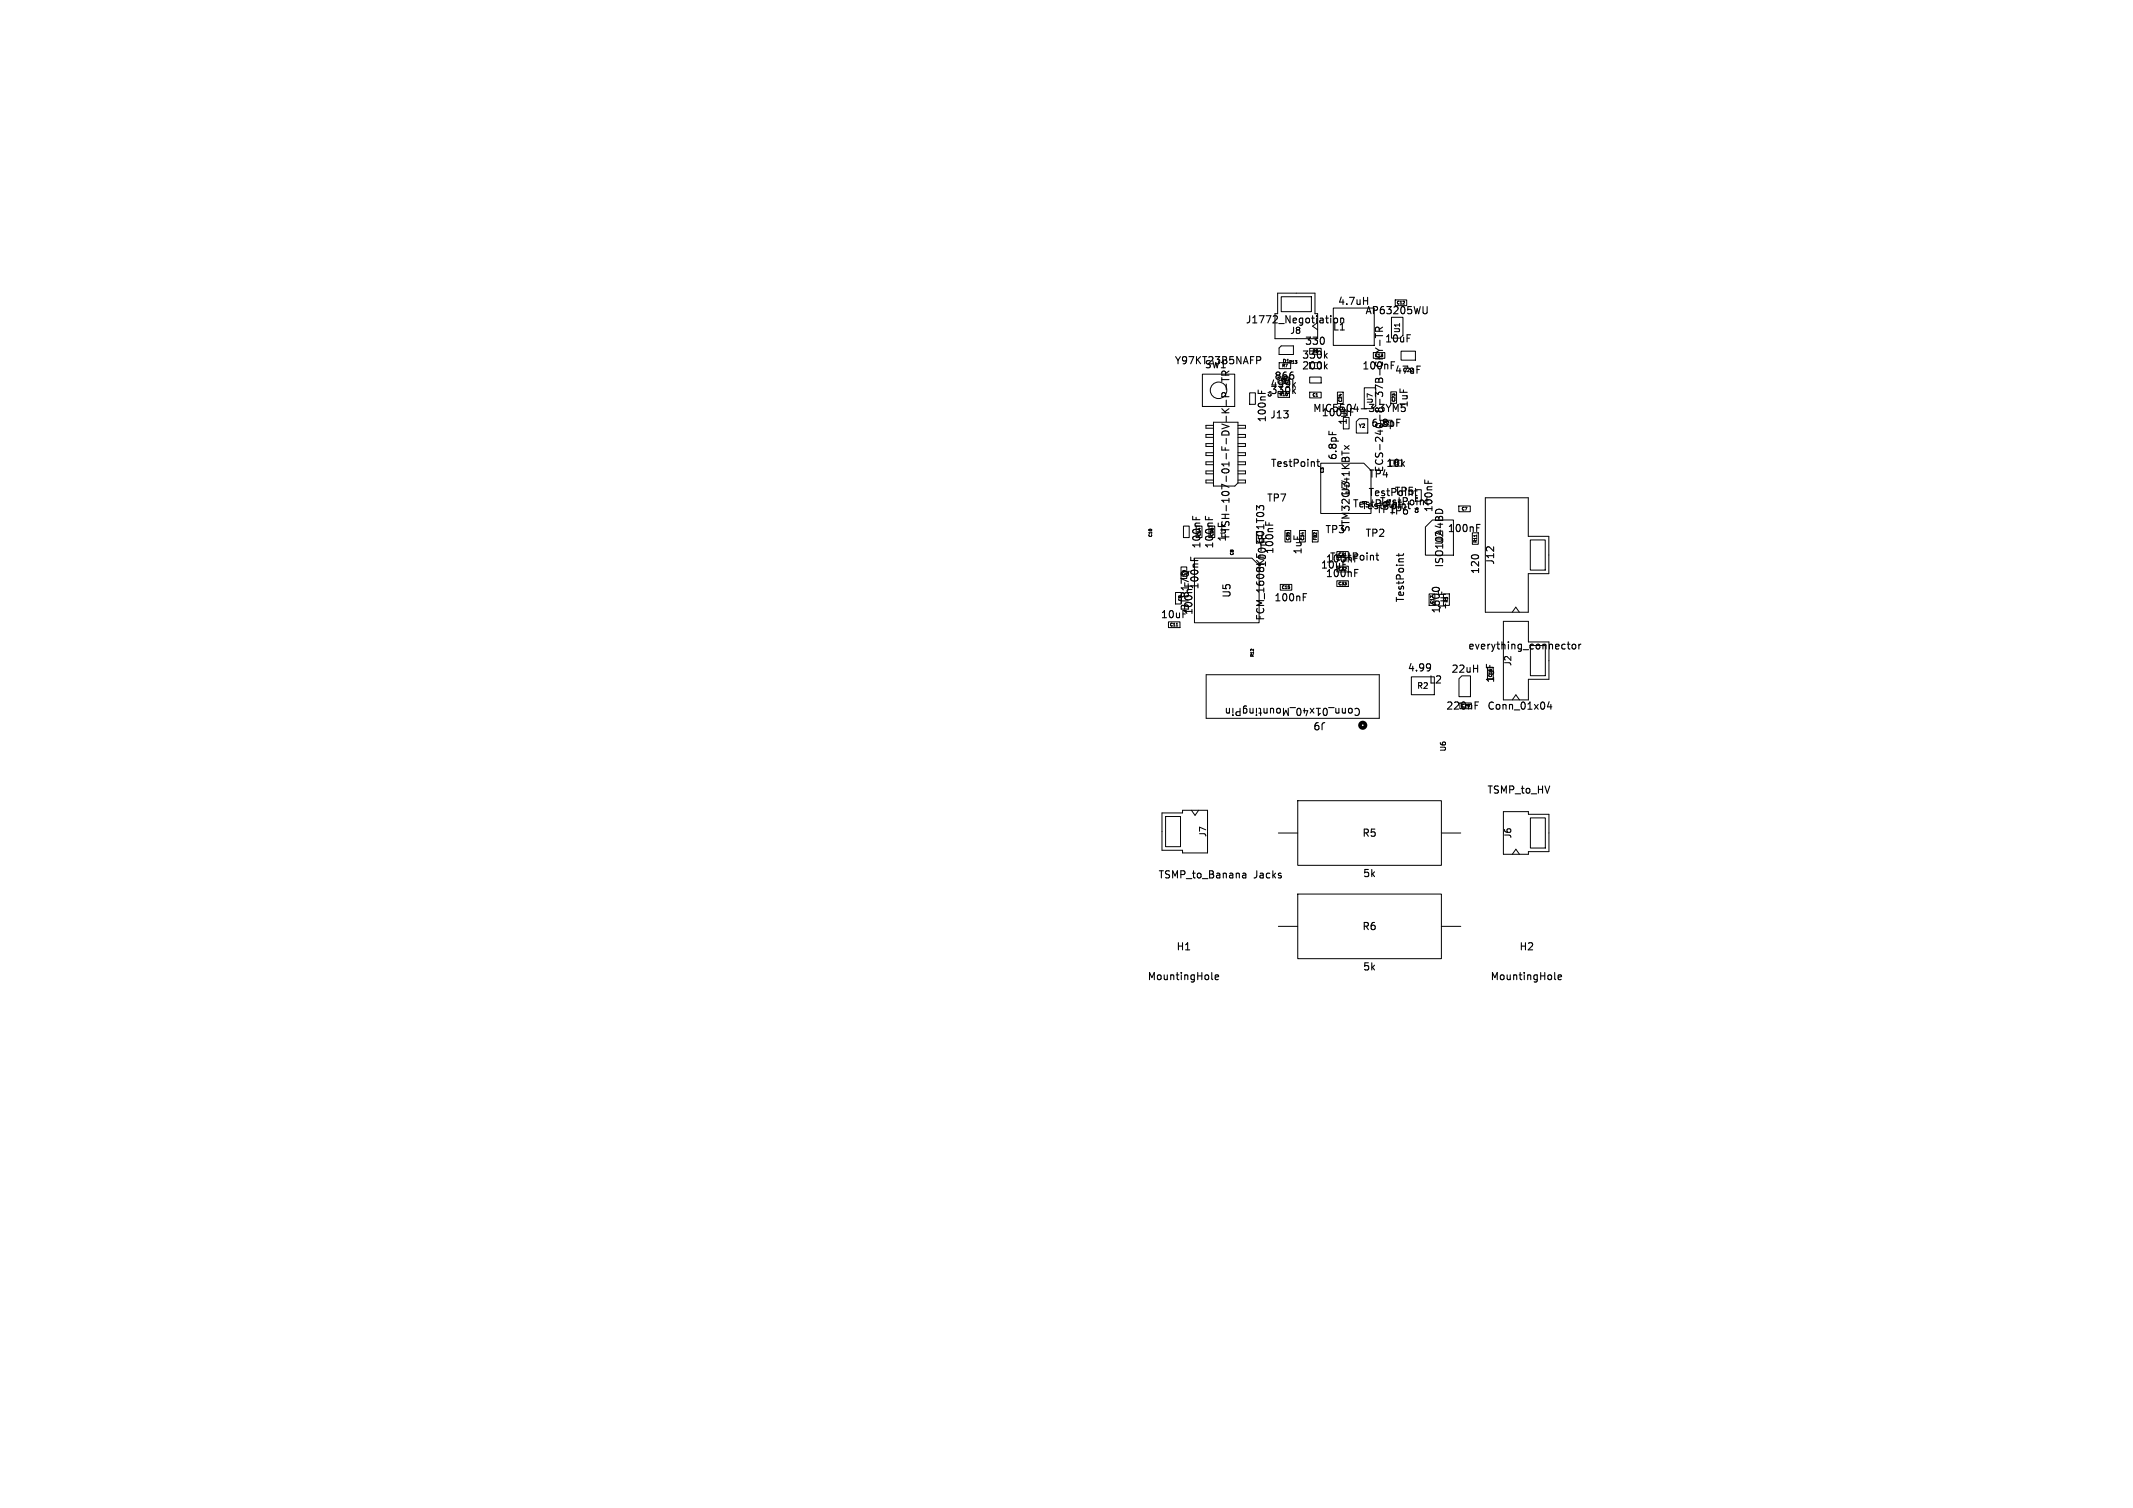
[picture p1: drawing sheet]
<svg xmlns="http://www.w3.org/2000/svg" width="297mm" height="210mm" viewBox="0 0 297 210" stroke-linecap="round" stroke-linejoin="round" font-family="sans-serif">
<defs><g id="words">
<g font-size="1.4">
<text x="173.4" y="45.2">J1772_Negotiation</text>
<text x="185.5" y="46.2">L1</text>
<text x="186.2" y="42.7">4.7uH</text>
<text x="190" y="44">AP63205WU</text>
<text x="192.8" y="47.9">10uF</text>
<text x="163.5" y="50.9">Y97KT23B5NAFP</text>
<text x="167.6" y="51.5">SW1</text>
<text x="177.4" y="53.1">866</text>
<text x="178.5" y="53.7">D</text>
<text x="181.2" y="50.2">330k</text>
<text x="181.2" y="51.7">200k</text>
<text x="181.6" y="48.2">330</text>
<text x="189.6" y="51.7">100nF</text>
<text x="194.1" y="52.3">47uF</text>
<text x="176.5" y="58.9" transform="rotate(-90 176.5 58.9)">100nF</text>
<text x="176.8" y="58.5">J13</text>
<text x="176.8" y="55.1">330k</text>
<text x="176.8" y="54.2">499k</text>
<text x="182.7" y="57.6">MIC5504-3.3YM5</text>
<text x="183.9" y="58.2">100nF</text>
<text x="187.7" y="59.3" transform="rotate(-90 187.7 59.3)">1uF</text>
<text x="190.8" y="59.7">6.8pF</text>
<text x="196.2" y="56.9" transform="rotate(-90 196.2 56.9)">1uF</text>
<text x="176.8" y="65.2">TestPoint</text>
<text x="186.3" y="64.2" transform="rotate(-90 186.3 64.2)">6.8pF</text>
<text x="192.8" y="65.9" transform="rotate(-90 192.8 65.9)">ECS-240-8-37B-CKY-TR</text>
<text x="192.9" y="65.2">10k</text>
<text x="176.3" y="70.1">TP7</text>
<text x="188.1" y="69.1" transform="rotate(-90 188.1 69.1)">U3</text>
<text x="188.3" y="70.9">TestPoint</text>
<text x="189.5" y="71.1">TestPoint</text>
<text x="190.4" y="69.3">TestPoint</text>
<text x="190.5" y="66.7">TP4</text>
<text x="191.6" y="71.7">TP1</text>
<text x="192" y="70.6">TestPoint</text>
<text x="193.3" y="71.9">TP6</text>
<text x="194.1" y="69.1">TP5</text>
<text x="199.7" y="71.4" transform="rotate(-90 199.7 71.4)">100nF</text>
<text x="167.3" y="76.5" transform="rotate(-90 167.3 76.5)">100nF</text>
<text x="169.1" y="76.5" transform="rotate(-90 169.1 76.5)">100nF</text>
<text x="170.9" y="75.5" transform="rotate(-90 170.9 75.5)">1uF</text>
<text x="171.4" y="75.1" transform="rotate(-90 171.4 75.1)">FTSH-107-01-F-DV-K-P-TR</text>
<text x="177.5" y="77.3" transform="rotate(-90 177.5 77.3)">100nF</text>
<text x="181.4" y="77.3" transform="rotate(-90 181.4 77.3)">1uF</text>
<text x="184.4" y="74.5">TP3</text>
<text x="188.1" y="74.2" transform="rotate(-90 188.1 74.2)">STM32G441KBTx</text>
<text x="190" y="75">TP2</text>
<text x="201.2" y="76" transform="rotate(-90 201.2 76)">U2</text>
<text x="201.5" y="74.3">100nF</text>
<text x="167.1" y="82.2" transform="rotate(-90 167.1 82.2)">100nF</text>
<text x="171.5" y="83.4" transform="rotate(-90 171.5 83.4)">U5</text>
<text x="176.5" y="79.1" transform="rotate(-90 176.5 79.1)">100nF</text>
<text x="177.3" y="83.9">100nF</text>
<text x="183.8" y="79.4">10uF</text>
<text x="184.5" y="80.6">100nF</text>
<text x="184.5" y="78.5">100nF</text>
<text x="185.1" y="78.3">TestPoint</text>
<text x="195.7" y="84" transform="rotate(-90 195.7 84)">TestPoint</text>
<text x="201.2" y="79.1" transform="rotate(-90 201.2 79.1)">ISO1044BD</text>
<text x="206.2" y="80.1" transform="rotate(-90 206.2 80.1)">120</text>
<text x="208.2" y="78.7" transform="rotate(-90 208.2 78.7)">J12</text>
<text x="161.5" y="86.3">10uF</text>
<text x="165.7" y="85.2" transform="rotate(-90 165.7 85.2)">BT817Q</text>
<text x="166.2" y="85.7" transform="rotate(-90 166.2 85.7)">100nF</text>
<text x="176.2" y="86.5" transform="rotate(-90 176.2 86.5)">FCM_1608KF-601T03</text>
<text x="200.7" y="85.5" transform="rotate(-90 200.7 85.5)">1600</text>
<text x="201.5" y="85" transform="rotate(-90 201.5 85)">1uF</text>
<text x="195.9" y="93.7">4.99</text>
<text x="198.9" y="95.4">L2</text>
<text x="202" y="93.9">22uH</text>
<text x="204.3" y="90.7">everything_connector</text>
<text x="208.2" y="95.2" transform="rotate(-90 208.2 95.2)">1uF</text>
<text x="184.7" y="100.4" transform="rotate(-180 184.7 100.4)">J9</text>
<text x="189.6" y="98.4" transform="rotate(-180 189.6 98.4)">Conn_01x40_MountingPin</text>
<text x="201.3" y="99">220nF</text>
<text x="207" y="99">Conn_01x04</text>
<text x="207" y="110.7">TSMP_to_HV</text>
<text x="189.6" y="116.7">R5</text>
<text x="161.2" y="122.5">TSMP_to_Banana</text>
<text x="174.6" y="122.5">Jacks</text>
<text x="189.7" y="122.4">5k</text>
<text x="189.6" y="129.7">R6</text>
<text x="159.7" y="136.7">MountingHole</text>
<text x="163.7" y="132.6">H1</text>
<text x="189.7" y="135.4">5k</text>
<text x="207.4" y="136.7">MountingHole</text>
<text x="211.5" y="132.6">H2</text>
</g>
<g font-size="1.2">
<text x="179.6" y="46.7">J8</text>
<text x="210.6" y="92.9" transform="rotate(-90 210.6 92.9)">J2</text>
<text x="168.1" y="116.7" transform="rotate(-90 168.1 116.7)">J7</text>
<text x="210.6" y="116.9" transform="rotate(-90 210.6 116.9)">J6</text>
</g>
<text font-size="1.1" x="197.2" y="96.1">R2</text>
<g font-size="1">
<text x="195.1" y="46.5" transform="rotate(-90 195.1 46.5)">U1</text>
<text x="191.3" y="56.3" transform="rotate(-90 191.3 56.3)">U7</text>
<text x="201.5" y="104.7" transform="rotate(-90 201.5 104.7)">U6</text>
</g>
<g font-size=".7">
<text x="178.5" y="50.7">D1</text>
<text x="195.3" y="51.9">C22</text>
<text x="189.1" y="59.7">Y2</text>
</g>
<g font-size=".6">
<text x="194.4" y="42.5">C12</text>
<text x="178.3" y="53.2">R9</text>
<text x="178.5" y="51.2">R7</text>
<text x="179.4" y="50.7">R13</text>
<text x="182.7" y="49.2">R8</text>
<text x="191.4" y="49.8">C13</text>
<text x="177.1" y="55.3" transform="rotate(-90 177.1 55.3)">C4</text>
<text x="178.1" y="55.2">R10</text>
<text x="182.7" y="55.3">C1</text>
<text x="186.9" y="56" transform="rotate(-90 186.9 56)">C24</text>
<text x="192.6" y="59.2">C2</text>
<text x="194.3" y="56" transform="rotate(-90 194.3 56)">C23</text>
<text x="184.4" y="65.9" transform="rotate(-90 184.4 65.9)">C3</text>
<text x="194" y="64.8">R1</text>
<text x="197.6" y="71.5" transform="rotate(-90 197.6 71.5)">C6</text>
<text x="203.5" y="71.2">C7</text>
<text x="160.5" y="74.8" transform="rotate(-90 160.5 74.8)">C10</text>
<text x="167.3" y="74.7" transform="rotate(-90 167.3 74.7)">C14</text>
<text x="169" y="74.7" transform="rotate(-90 169 74.7)">C26</text>
<text x="171.8" y="77.4" transform="rotate(-90 171.8 77.4)">C8</text>
<text x="179.6" y="75.3" transform="rotate(-90 179.6 75.3)">C35</text>
<text x="181.6" y="75.3" transform="rotate(-90 181.6 75.3)">C34</text>
<text x="183.4" y="75.3" transform="rotate(-90 183.4 75.3)">FB2</text>
<text x="186.3" y="77.5">C31</text>
<text x="205.7" y="75.6" transform="rotate(-90 205.7 75.6)">R11</text>
<text x="164.6" y="83.8" transform="rotate(-90 164.6 83.8)">C9</text>
<text x="165.1" y="80.2" transform="rotate(-90 165.1 80.2)">C5</text>
<text x="178.4" y="82.1">C15</text>
<text x="186.3" y="81.6">C33</text>
<text x="186.3" y="79.5">C32</text>
<text x="201.7" y="83.9" transform="rotate(-90 201.7 83.9)">R3</text>
<text x="162.9" y="87.3">C11</text>
<text x="199.7" y="84.1" transform="rotate(-90 199.7 84.1)">C17</text>
<text x="174.7" y="91.5" transform="rotate(-90 174.7 91.5)">R12</text>
<text x="207.8" y="94.4" transform="rotate(-90 207.8 94.4)">C16</text>
<text x="203.4" y="98.6">C29</text>
</g>
</g></defs>
<g fill="none" stroke="#000" stroke-width=".15">
<path d="M170.1 56.9l.6 .6M170.1 51.9v.3h1M170.1 52.6v.6M170.1 52.9h1M170.6 55.2v-.4l-.1-.1h-.3l-.1 .5h1M170.6 51.9v.3M170.7 53.5v.7M170.7 55.7v.8M171.1 56.9l-.5 .4M171.1 51.7l-.5 .3M175 49.7h.4l.2 .2-.1 .2-.5 .1M175.2 54.3v.5"/>
<path d="M175.7 54.5v.3M180.1 52.3v.4M180.1 54.4l.3 .4M180.1 53.6l.3 .3M180.4 54.1l-.4 .4M180.4 53.3l-.4 .4M184.4 47.1v.7M184.5 49.5l.3 .4M184.5 51l.3 .4M184.8 49.2l-.4 .4M184.8 50.7l-.4 .4M185.7 44.8v-.3l.2-.2 .3 .1v.4"/>
<path d="M186.7 44.4l.1-.1h.3v.7M186.7 44.3v.7M189.9 41.9h.5M190.4 41.4v1M191.5 48.5l.5 .3M191.5 46.5v.5M191.5 46.7h1M192 48.8h.5M192 48.8l-.5 .3M192 46.1v-.4l-.1-.1h-.3l-.1 .5h1M192.1 47.4v.7M192.5 45.6l-.5 .3"/>
<path d="M193.7 50.4h.5M194 56.3l.3 .7 .4-.7v1M194.5 58.4h.5M195.7 57.1l-.2 .2-.4-.1M195.9 46.6h.5M197.3 51h.5M198.7 42.7v.8l-.1 .1-.3 .1M165.6 79.5l-.1 .1M165.8 77.6v.5M166.1 71.9v.5M166.3 77.7v.4M166.5 72v.4"/>
<path d="M167.8 71.9v.5M168.3 72v.4M175 72.2v.6M175.1 71.5a.54 .54 0 0 1 .9 .2 .57 .57 0 0 1-1-.1zM175.9 70.5h-.5l-.1 .2-.3-.3v.6M175.9 70.5l.1 .4-.1 .1M183.4 64.3h.3M183.5 64v.8l.2 .2M185 60v.5M187.2 62.1l.7 .5M187.9 62.1l-.7 .5M188.6 79.8h.4"/>
<path d="M188.6 79.3h.5M191.6 77.3h.4M191.7 77v.9l.3 .1M194.8 77.1v.4M195.4 77.1l-.1 .2h-.9M197 68.4h.3M197.1 68v.9l.2 .1M198.4 66.8v.5M198.9 67v.3M200.1 71l.4-.1 .2 .1 .2 .5M205.1 77.3h.6M205.6 73.5h.3"/>
<path d="M205.6 73h.5M170.8 98.6v.7h.2l.2-.1M171.2 98.6v.7M171.7 98.6v.7M171.7 99.5v.1M172.7 98.6v1l-.6-.1v-.2l.1-.1 .5-.1M181.5 83.1h.3M181.5 82.7h.4M199 92.4l.1 .1a.84 .84 0 0 1-.1 .8M199.2 92.9l-.2 .2M199.4 82a.63 .63 0 0 1 1 0M205.2 93.1h.5"/>
<path d="M205.4 98.2h.3M205.4 97.8h.5M205.7 92.6v1M215.7 97.7l-.2 .7h.6M215.9 98.1v.7M218.2 89.7h.4M218.4 89.4v.8l.2 .2M219 89.8l.2-.1 .2 .2v.3l-.2 .2-.2-.1-.1-.1zM219.8 89.7v.7M220.1 89.7l-.3 .2M168.7 135.4v.9l.2 .1M169.2 136.1l.5-.1-.1-.2h-.3l-.1 .1 .1 .5h.3"/>
<path d="M173 122.1l.1 .2 .4-.1M173 121.6h.4l.1 .7M173.5 121.8l-.4 .1-.1 .1M216.5 135.4v.9l.1 .1M217 136.1l.4-.1v-.2h-.3l-.1 .1v.5h.4"/>
</g>
<g fill="none" stroke="#000" stroke-width=".14">
<path d="M167.4 52.1h4.5v4.5h-4.5zM169 59.2h-1.1v.4h1.1M169 58.8h3.4v8.5l-.5 .4h-2.9zM172.4 59.2h1v.4h-1M174 54.7h.8v1.6h-.8zM177.9 40.8h5.2v2.9h.4v3.5h-6v-3.5h.4zM178.1 50.5h1.6v.8h-1.6zM178.4 48.2h1.7v1.2h-2v-.9zM178.4 41.3h4.2v2.1h-4.2zM182.4 52.5h1.6v.8h-1.6zM182.4 48.5h1.6v.8h-1.6zM182.4 54.6h1.6v.8h-1.6z"/>
<path d="M185.7 42.9h5.7v5.2h-5.7zM186.2 54.6h.8v1.6h-.8zM187.1 58.1h.8v1.6h-.8zM188.9 58.7l.4-.4h1.2v2h-1.6zM190 54h1.6v2.5l-.4 .4h-1.2zM191.2 49.1h1.6v.8h-1.6zM193.7 54.6h.8v1.6h-.8zM193.8 44.2h1.5v2.5l-.4 .4h-1.1zM194.3 41.8h1.6v.8h-1.6zM195.1 48.9h2v1.3h-2zM164.4 79h.8v1.6h-.8zM164.8 73.3h.8v1.6h-.8z"/>
<path d="M166.3 77.7h8l1 1v8h-9zM169 60.5h-1.1v.4h1.1M169 61.8h-1.1v.4h1.1M169 63h-1.1v.4h1.1M169 64.3h-1.1v.4h1.1M169 65.6h-1.1v.4h1.1M169 66.9h-1.1v.4h1.1M172.4 60.5h1v.4h-1M172.4 61.8h1v.4h-1M172.4 63h1v.4h-1M172.4 64.3h1v.4h-1M172.4 65.6h1v.4h-1"/>
<path d="M172.4 66.9h1v.4h-1M178.9 73.9h.8v1.6h-.8zM181 73.9h.8v1.6h-.8zM182.7 73.9h.8v1.6h-.8zM183.9 64.5h6l1 1v6h-7zM186.1 78.8h1.6v.8h-1.6zM197.1 68.2h.8v1.6h-.8zM198.5 73.4l1-1h2.9v4.9h-3.9zM203.1 70.5h1.6v.8h-1.6zM205 74.2h.8v1.6h-.8zM206.8 69.3h6v5.4h2.9v5.2h-2.9v5.4h-6zM213.1 75.2h2.1v4.2h-2.1z"/>
<path d="M162.7 86.6h1.6v.8h-1.6zM163.7 82.5h.8v1.6h-.8zM163.8 87.2h.2M167.9 94h24.2v6h-24.2zM178.3 81.4h1.6v.8h-1.6zM186.1 80.9h1.6v.8h-1.6zM196.5 94.3h3.2v2.4h-3.2zM199 82.7h.8v1.6h-.8zM203.6 94.1h1.2v2.9h-1.6v-2.5zM209.3 86.5h3.5v2.9h2.9v5.2h-2.9v2.9h-3.5zM210.6 85.3l.5-.7 .5 .7M210.6 97.5l.5-.7 .5 .7"/>
<path d="M213.1 89.9h2.1v4.2h-2.1zM161.8 113.2h2.9v-.4h3.4v6h-3.4v-.4h-2.9zM162.3 113.7h2.1v4.2h-2.1zM165.9 112.8l.5 .7 .5-.7M178 116h2.7M180.7 111.5h20v9h-20zM200.7 116h2.7M209.3 113h3.5v.4h2.9v5.2h-2.9v.4h-3.5zM210.6 119l.5-.7 .5 .7M213.1 113.9h2.1v4.2h-2.1zM178 129h2.7M180.7 124.5h20v9h-20z"/>
<path d="M200.7 129h2.7"/>
<circle cx="169.7" cy="54.4" r="1.15"/>
</g>
<circle cx="189.7" cy="101" r=".38" fill="none" stroke="#000" stroke-width=".51"/>
<use href="#words"/>
</svg>
